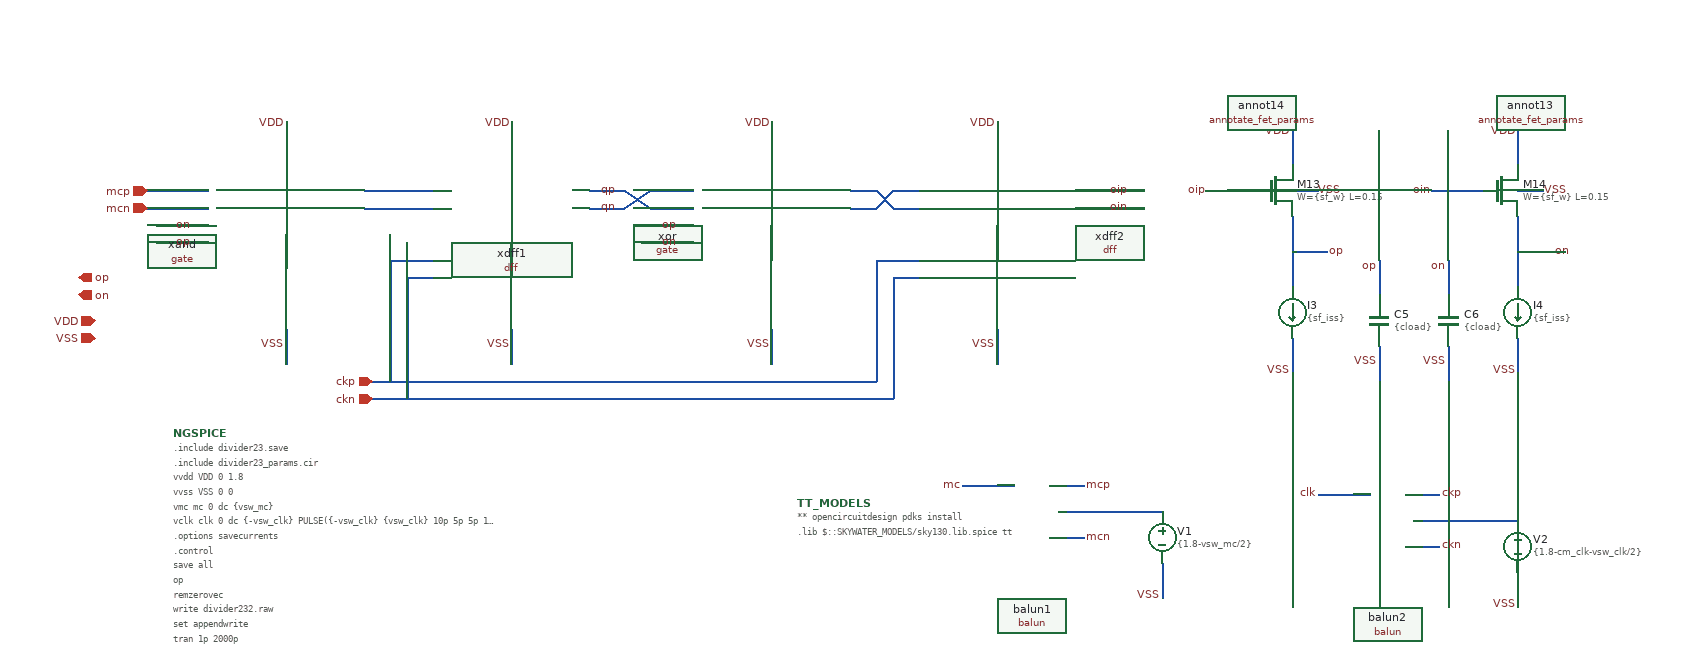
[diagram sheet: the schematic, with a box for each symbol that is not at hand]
v {xschem version=3.4.8RC file_version=1.3}
G {}
K {}
V {}
S {}
F {}
E {}
B 2 1230 -830 2140 -460 {flags=graph
digital=0
y1=-0.5
y2=0.5
divy=5
x1=0
x2=2e-09
ypos1=0
ypos2=0.5
divx=10
subdivx=1
dataset=0
unitx=1
 subdivy=1
legend=1
unity=1
color="7 21 4 12 10"
node="\\"ckp ckn -\\"
\\"op on -\\"
\\"qp qn -\\"
\\"oip oin -\\"
\\"mcp mcn -\\""
sim_type=tran
rawfile=$netlist_dir/divider23.raw
logy=0
hilight_wave=-1
linewidth_mult=2
rainbow=0}
B 2 300 -830 1210 -460 {flags=graph
digital=0
y1=-0.5
y2=0.5
divy=5
x1=0
x2=2e-09
ypos1=0
ypos2=0.5
divx=10
subdivx=1
dataset=0
unitx=1
 subdivy=1
legend=1
unity=1
color="7 21 4 12 10"
node="\\"ckp ckn -\\"
\\"op on -\\"
\\"qp qn -\\"
\\"oip oin -\\"
\\"mcp mcn -\\""
sim_type=tran
rawfile=$netlist_dir/divider232.raw
logy=0
hilight_wave=-1
linewidth_mult=2
rainbow=0}
N 1850 130 1890 130 {lab=ckn}
N 1850 70 1890 70 {lab=ckp}
N 1750 70 1810 70 {lab=clk}
N 1860 100 1980 100 {lab=#net1}
N 1980 160 1980 200 {lab=VSS}
N 1720 -110 1720 -70 {lab=VSS}
N 1720 -200 1720 -170 {lab=op}
N 1720 -250 1720 -200 {lab=op}
N 1720 -280 1750 -280 {lab=VSS}
N 1720 -350 1720 -310 {lab=VDD}
N 1720 -210 1760 -210 {lab=op}
N 1620 -280 1680 -280 {lab=oip}
N 1980 -110 1980 -70 {lab=VSS}
N 1980 -200 1980 -170 {lab=on}
N 1980 -250 1980 -200 {lab=on}
N 1980 -280 2010 -280 {lab=VSS}
N 1980 -350 1980 -310 {lab=VDD}
N 1980 -210 2020 -210 {lab=on}
N 1880 -280 1940 -280 {lab=oin}
N 1820 -200 1820 -160 {lab=op}
N 1820 -100 1820 -60 {lab=VSS}
N 1900 -200 1900 -160 {lab=on}
N 1900 -100 1900 -60 {lab=VSS}
N 650 -280 730 -280 {lab=#net2}
N 650 -260 730 -260 {lab=#net3}
N 1470 -280 1550 -280 {lab=oip}
N 1470 -260 1550 -260 {lab=oin}
N 970 -240 1030 -240 {lab=op}
N 980 -220 1030 -220 {lab=on}
N 970 -220 980 -220 {lab=on}
N 410 -240 470 -240 {lab=on}
N 420 -220 470 -220 {lab=op}
N 410 -220 420 -220 {lab=op}
N 680 -160 680 -60 {lab=ckp}
N 690 -200 730 -200 {lab=ckp}
N 1270 -180 1290 -180 {lab=ckn}
N 710 -180 730 -180 {lab=ckn}
N 700 -140 700 -40 {lab=ckn}
N 1240 -200 1240 -100 {lab=ckp}
N 1250 -200 1290 -200 {lab=ckp}
N 670 -60 1240 -60 {lab=ckp}
N 1260 -180 1270 -180 {lab=ckn}
N 1240 -200 1250 -200 {lab=ckp}
N 1240 -100 1240 -60 {lab=ckp}
N 1260 -180 1260 -40 {lab=ckn}
N 670 -40 1260 -40 {lab=ckn}
N 660 -60 670 -60 {lab=ckp}
N 660 -40 670 -40 {lab=ckn}
N 680 -200 680 -160 {lab=ckp}
N 680 -200 690 -200 {lab=ckp}
N 700 -180 710 -180 {lab=ckn}
N 700 -180 700 -140 {lab=ckn}
N 1120 -120 1120 -80 {lab=VSS}
N 820 -120 820 -80 {lab=VSS}
N 560 -120 560 -80 {lab=VSS}
N 1380 -120 1380 -80 {lab=VSS}
N 400 -280 470 -280 {lab=mcp}
N 400 -260 470 -260 {lab=mcn}
N 1120 -360 1120 -320 {lab=VDD}
N 820 -360 820 -320 {lab=VDD}
N 560 -360 560 -320 {lab=VDD}
N 1380 -360 1380 -320 {lab=VDD}
N 980 -280 1030 -280 {lab=qn}
N 950 -260 980 -280 {lab=qn}
N 910 -260 950 -260 {lab=qn}
N 910 -280 950 -280 {lab=qp}
N 950 -280 980 -260 {lab=qp}
N 980 -260 1030 -260 {lab=qp}
N 1210 -280 1240 -280 {lab=#net4}
N 1240 -280 1260 -260 {lab=#net4}
N 1260 -260 1290 -260 {lab=#net4}
N 1260 -280 1290 -280 {lab=#net5}
N 1240 -260 1260 -280 {lab=#net5}
N 1210 -260 1240 -260 {lab=#net5}
N 1440 120 1480 120 {lab=mcn}
N 1440 60 1480 60 {lab=mcp}
N 1340 60 1400 60 {lab=mc}
N 1450 90 1570 90 {lab=#net6}
N 1570 150 1570 190 {lab=VSS}
C {devices/code.sym} 1150 80 0 0 {name=TT_MODELS
only_toplevel=true
format="tcleval( @value )"
value="
** opencircuitdesign pdks install
.lib $::SKYWATER_MODELS/sky130.lib.spice tt
"
spice_ignore=false}
C {iopin.sym} 340 -110 2 0 {name=p1 lab=VSS}
C {iopin.sym} 340 -130 2 0 {name=p4 lab=VDD}
C {opin.sym} 320 -180 0 0 {name=p14 lab=op}
C {opin.sym} 320 -160 0 0 {name=p15 lab=on}
C {devices/code_shown.sym} 430 0 0 0 {name=NGSPICE
only_toplevel=true
value="
.include divider23.save
.include divider23_params.cir
vvdd VDD 0 1.8
vvss VSS 0 0
vmc mc 0 dc \{vsw_mc\}
vclk clk 0 dc \{-vsw_clk\} PULSE(\{-vsw_clk\} \{vsw_clk\} 10p 5p 5p 145p 300p)
.options savecurrents
.control
save all
op
remzerovec 
write divider232.raw
set appendwrite
tran 1p 2000p
let x = v(ckp)-v(ckn)
let y = v(op)-v(on)
meas tran tdiff TRIG x VAL=0 RISE=3 TARG y VAL=0 RISE=2
write divider232.raw
.endc
" }
C {devices/launcher.sym} 1220 290 0 0 {name=h4 
descr="Load/unload
waveforms" 
tclcommand="
xschem raw_read $netlist_dir/divider23.raw tran
"
}
C {devices/launcher.sym} 1220 240 0 0 {name=h1
descr="Annotate OP" 
tclcommand="set show_hidden_texts 1; xschem annotate_op"
}
C {ipin.sym} 660 -60 0 0 {name=p30 lab=ckp}
C {ipin.sym} 660 -40 0 0 {name=p31 lab=ckn}
C {/foss/designs/balun/balun.sym} 1830 100 0 0 {name=balun2}
C {lab_pin.sym} 1890 130 0 1 {name=p32 lab=ckn}
C {lab_pin.sym} 1890 70 0 1 {name=p33 lab=ckp}
C {lab_pin.sym} 1750 70 0 0 {name=p34 lab=clk}
C {vsource.sym} 1980 130 0 0 {name=V2 value=\{1.8-cm_clk-vsw_clk/2\} savecurrent=true}
C {lab_pin.sym} 1980 197.565430272133 3 0 {name=p36 lab=VSS}
C {lab_pin.sym} 1760 -210 2 0 {name=p43 lab=op}
C {sky130_fd_pr/nfet_01v8_lvt.sym} 1700 -280 0 0 {name=M13
L=0.15
W=\{sf_w\}
nf=\{sf_nf\}
mult=1
model=nfet_01v8_lvt
spiceprefix=X
}
C {lab_pin.sym} 1720 -72.434569727867 3 0 {name=p55 lab=VSS}
C {isource.sym} 1720 -140 0 0 {name=I3 value=\{sf_iss\}
}
C {lab_wire.sym} 1747.565430272133 -280 0 1 {name=p56 lab=VSS
}
C {lab_pin.sym} 1720 -347.5654302721329 1 0 {name=p57 lab=VDD}
C {lab_wire.sym} 1622.434569727867 -280 0 0 {name=p58 lab=oip}
C {lab_pin.sym} 2020 -210 2 0 {name=p59 lab=on}
C {lab_pin.sym} 1980 -72.434569727867 3 0 {name=p60 lab=VSS}
C {isource.sym} 1980 -140 0 0 {name=I4 value=\{sf_iss\}
}
C {lab_wire.sym} 2007.565430272133 -280 0 1 {name=p61 lab=VSS
}
C {lab_pin.sym} 1980 -347.5654302721329 1 0 {name=p62 lab=VDD}
C {lab_wire.sym} 1882.434569727867 -280 0 0 {name=p63 lab=oin}
C {capa.sym} 1820 -130 0 0 {name=C5
m=1
value=\{cload\}
footprint=1206
device="ceramic capacitor"}
C {lab_wire.sym} 1820 -82.434569727867 3 0 {name=p12 lab=VSS}
C {lab_wire.sym} 1820 -192.434569727867 3 0 {name=p13 lab=op}
C {capa.sym} 1900 -130 0 0 {name=C6
m=1
value=\{cload\}
footprint=1206
device="ceramic capacitor"}
C {lab_wire.sym} 1900 -82.434569727867 3 0 {name=p16 lab=VSS}
C {lab_wire.sym} 1900 -192.434569727867 3 0 {name=p17 lab=on}
C {sky130_fd_pr/nfet_01v8_lvt.sym} 1960 -280 0 0 {name=M14
L=0.15
W=\{sf_w\}
nf=\{sf_nf\}
mult=1
model=nfet_01v8_lvt
spiceprefix=X
}
C {sky130_fd_pr/annotate_fet_params.sym} 2040 -420 0 0 {name=annot13 ref=M14}
C {sky130_fd_pr/annotate_fet_params.sym} 1740 -430 0 0 {name=annot14 ref=M13}
C {/foss/designs/divider23/dff.sym} 1380 -220 0 0 {name=xdff2
+ latch1_winp=\{dff2_latch1_winp\} latch1_wclk=\{dff2_latch1_wclk\} latch1_wlat=\{dff2_latch1_wlat\} latch1_nfinp=\{dff2_latch1_nfinp\} latch1_nfclk=\{dff2_latch1_nfclk\} latch1_nflat=\{dff2_latch1_nflat\} latch1_vsw=\{dff2_latch1_vsw\} latch1_iss=\{dff2_latch1_iss\} latch2_winp=\{dff2_latch2_winp\} latch2_wclk=\{dff2_latch2_wclk\} latch2_wlat=\{dff2_latch2_wlat\} latch2_nfinp=\{dff2_latch2_nfinp\} latch2_nfclk=\{dff2_latch2_nfclk\} latch2_nflat=\{dff2_latch2_nflat\} latch2_vsw=\{dff2_latch2_vsw\} latch2_iss=\{dff2_latch2_iss\}}
C {/foss/designs/divider23/gate.sym} 1120 -220 0 0 {name=xor
+ win1=\{or_win1\} win2=\{or_win2\} nfin1=\{or_nfin1\} nfin2=\{or_nfin2\} vsw=\{or_vsw\} iss=\{or_iss\}}
C {/foss/designs/divider23/gate.sym} 560 -220 0 0 {name=xand
+ win1=\{and_win1\} win2=\{and_win2\} nfin1=\{and_nfin1\} nfin2=\{and_nfin2\} vsw=\{and_vsw\} iss=\{and_iss\}}
C {lab_wire.sym} 1532.434569727867 -280 0 0 {name=p2 lab=oip}
C {lab_wire.sym} 1532.434569727867 -260 0 0 {name=p3 lab=oin}
C {lab_wire.sym} 1012.434569727867 -220 0 0 {name=p5 lab=on}
C {lab_wire.sym} 1012.434569727867 -240 0 0 {name=p6 lab=op}
C {lab_wire.sym} 452.434569727867 -240 0 0 {name=p7 lab=on}
C {lab_wire.sym} 452.434569727867 -220 0 0 {name=p8 lab=op}
C {ipin.sym} 400 -280 0 0 {name=p9 lab=mcp}
C {ipin.sym} 400 -260 0 0 {name=p10 lab=mcn}
C {lab_wire.sym} 1120 -102.434569727867 3 0 {name=p11 lab=VSS}
C {lab_wire.sym} 820 -102.434569727867 3 0 {name=p18 lab=VSS}
C {lab_wire.sym} 560 -102.434569727867 3 0 {name=p19 lab=VSS}
C {lab_wire.sym} 1380 -102.434569727867 3 0 {name=p20 lab=VSS}
C {lab_pin.sym} 1120 -357.5654302721329 1 0 {name=p21 lab=VDD}
C {lab_pin.sym} 820 -357.5654302721329 1 0 {name=p22 lab=VDD}
C {lab_pin.sym} 560 -357.5654302721329 1 0 {name=p23 lab=VDD}
C {lab_pin.sym} 1380 -357.5654302721329 1 0 {name=p24 lab=VDD}
C {/foss/designs/divider23/dff.sym} 820 -220 0 0 {name=xdff1
+ latch1_winp=\{dff1_latch1_winp\} latch1_wclk=\{dff1_latch1_wclk\} latch1_wlat=\{dff1_latch1_wlat\} latch1_nfinp=\{dff1_latch1_nfinp\} latch1_nfclk=\{dff1_latch1_nfclk\} latch1_nflat=\{dff1_latch1_nflat\} latch1_vsw=\{dff1_latch1_vsw\} latch1_iss=\{dff1_latch1_iss\} latch2_winp=\{dff1_latch2_winp\} latch2_wclk=\{dff1_latch2_wclk\} latch2_wlat=\{dff1_latch2_wlat\} latch2_nfinp=\{dff1_latch2_nfinp\} latch2_nfclk=\{dff1_latch2_nfclk\} latch2_nflat=\{dff1_latch2_nflat\} latch2_vsw=\{dff1_latch2_vsw\} latch2_iss=\{dff1_latch2_iss\}}
C {/foss/designs/balun/balun.sym} 1420 90 0 0 {name=balun1}
C {lab_pin.sym} 1480 120 0 1 {name=p25 lab=mcn}
C {lab_pin.sym} 1480 60 0 1 {name=p26 lab=mcp}
C {lab_pin.sym} 1340 60 0 0 {name=p27 lab=mc}
C {vsource.sym} 1570 120 0 0 {name=V1 value=\{1.8-vsw_mc/2\} savecurrent=true}
C {lab_pin.sym} 1570 187.565430272133 3 0 {name=p28 lab=VSS}
C {lab_wire.sym} 942.434569727867 -260 0 0 {name=p29 lab=qn}
C {lab_wire.sym} 942.434569727867 -280 0 0 {name=p35 lab=qp}
